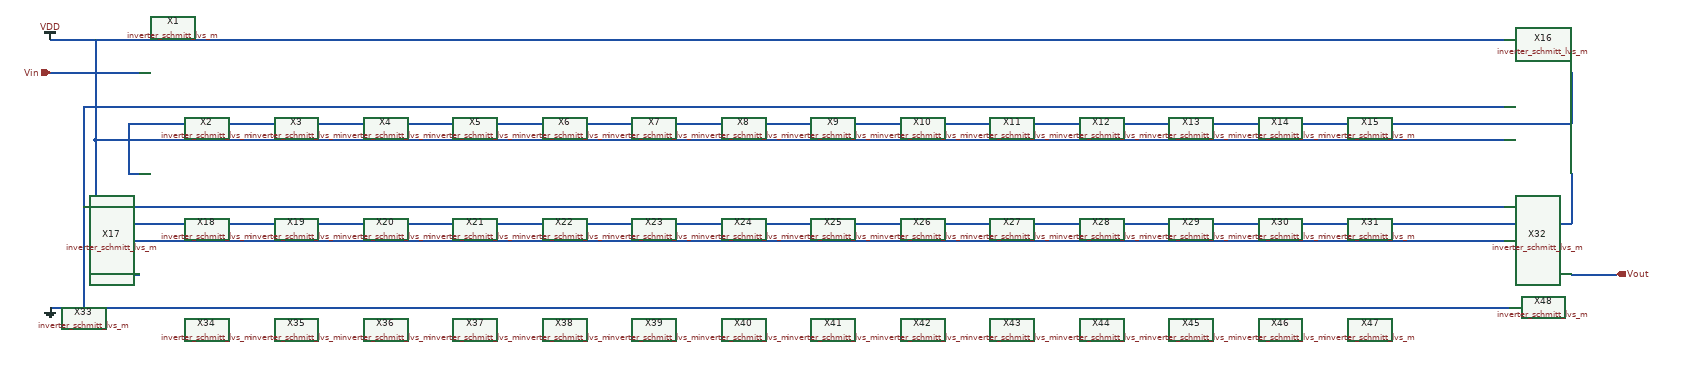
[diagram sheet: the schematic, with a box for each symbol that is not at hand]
v {xschem version=2.9.9 file_version=1.2 }
G {}
K {}
V {}
S {}
E {}
N 80 -540 2680 -540 { lab=VDD}
N 160 -360 2680 -360 { lab=VDD}
N 160 -540 160 -360 { lab=VDD}
N 160 -180 2680 -180 { lab=VDD}
N 160 -360 160 -180 { lab=VDD}
N 140 -420 280 -420 { lab=GND}
N 280 -420 2680 -420 { lab=GND}
N 140 -240 2680 -240 { lab=GND}
N 80 -60 2690 -60 { lab=GND}
N 140 -420 140 -60 { lab=GND}
N 2800 -480 2800 -390 { lab=#net1}
N 220 -390 2800 -390 { lab=#net1}
N 220 -390 220 -300 { lab=#net1}
N 220 -300 230 -300 { lab=#net1}
N 230 -300 240 -300 { lab=#net1}
N 2800 -300 2800 -210 { lab=#net2}
N 230 -210 2800 -210 { lab=#net2}
N 220 -210 230 -210 { lab=#net2}
N 220 -210 220 -120 { lab=#net2}
N 230 -120 240 -120 { lab=#net2}
N 220 -120 230 -120 { lab=#net2}
N 2800 -120 2880 -120 { lab=Vout}
N 80 -480 240 -480 { lab=Vin}
C {devices/ipin.sym} 80 -480 0 0 {name=p1 lab=Vin}
C {devices/opin.sym} 2880 -120 0 0 {name=p4 lab=Vout}
C {madvlsi/vdd.sym} 80 -540 0 0 {name=l1 lab=VDD}
C {madvlsi/gnd.sym} 80 -60 0 0 {name=l2 lab=GND}
C {/home/madvlsi/Desktop/MADVLSI_final/schematics/inverter_schmitt_lvs_m.sym} 200 -380 0 0 {name=X1}
C {/home/madvlsi/Desktop/MADVLSI_final/schematics/inverter_schmitt_lvs_m.sym} 360 -380 0 0 {name=X2}
C {/home/madvlsi/Desktop/MADVLSI_final/schematics/inverter_schmitt_lvs_m.sym} 520 -380 0 0 {name=X3}
C {/home/madvlsi/Desktop/MADVLSI_final/schematics/inverter_schmitt_lvs_m.sym} 680 -380 0 0 {name=X4}
C {/home/madvlsi/Desktop/MADVLSI_final/schematics/inverter_schmitt_lvs_m.sym} 840 -380 0 0 {name=X5}
C {/home/madvlsi/Desktop/MADVLSI_final/schematics/inverter_schmitt_lvs_m.sym} 1000 -380 0 0 {name=X6}
C {/home/madvlsi/Desktop/MADVLSI_final/schematics/inverter_schmitt_lvs_m.sym} 1160 -380 0 0 {name=X7}
C {/home/madvlsi/Desktop/MADVLSI_final/schematics/inverter_schmitt_lvs_m.sym} 1320 -380 0 0 {name=X8}
C {/home/madvlsi/Desktop/MADVLSI_final/schematics/inverter_schmitt_lvs_m.sym} 1480 -380 0 0 {name=X9}
C {/home/madvlsi/Desktop/MADVLSI_final/schematics/inverter_schmitt_lvs_m.sym} 1640 -380 0 0 {name=X10}
C {/home/madvlsi/Desktop/MADVLSI_final/schematics/inverter_schmitt_lvs_m.sym} 1800 -380 0 0 {name=X11}
C {/home/madvlsi/Desktop/MADVLSI_final/schematics/inverter_schmitt_lvs_m.sym} 1960 -380 0 0 {name=X12}
C {/home/madvlsi/Desktop/MADVLSI_final/schematics/inverter_schmitt_lvs_m.sym} 2120 -380 0 0 {name=X13}
C {/home/madvlsi/Desktop/MADVLSI_final/schematics/inverter_schmitt_lvs_m.sym} 2280 -380 0 0 {name=X14}
C {/home/madvlsi/Desktop/MADVLSI_final/schematics/inverter_schmitt_lvs_m.sym} 2440 -380 0 0 {name=X15}
C {/home/madvlsi/Desktop/MADVLSI_final/schematics/inverter_schmitt_lvs_m.sym} 2600 -380 0 0 {name=X16}
C {/home/madvlsi/Desktop/MADVLSI_final/schematics/inverter_schmitt_lvs_m.sym} 200 -200 0 0 {name=X17}
C {/home/madvlsi/Desktop/MADVLSI_final/schematics/inverter_schmitt_lvs_m.sym} 360 -200 0 0 {name=X18}
C {/home/madvlsi/Desktop/MADVLSI_final/schematics/inverter_schmitt_lvs_m.sym} 520 -200 0 0 {name=X19}
C {/home/madvlsi/Desktop/MADVLSI_final/schematics/inverter_schmitt_lvs_m.sym} 680 -200 0 0 {name=X20}
C {/home/madvlsi/Desktop/MADVLSI_final/schematics/inverter_schmitt_lvs_m.sym} 840 -200 0 0 {name=X21}
C {/home/madvlsi/Desktop/MADVLSI_final/schematics/inverter_schmitt_lvs_m.sym} 1000 -200 0 0 {name=X22}
C {/home/madvlsi/Desktop/MADVLSI_final/schematics/inverter_schmitt_lvs_m.sym} 1160 -200 0 0 {name=X23}
C {/home/madvlsi/Desktop/MADVLSI_final/schematics/inverter_schmitt_lvs_m.sym} 1320 -200 0 0 {name=X24}
C {/home/madvlsi/Desktop/MADVLSI_final/schematics/inverter_schmitt_lvs_m.sym} 1480 -200 0 0 {name=X25}
C {/home/madvlsi/Desktop/MADVLSI_final/schematics/inverter_schmitt_lvs_m.sym} 1640 -200 0 0 {name=X26}
C {/home/madvlsi/Desktop/MADVLSI_final/schematics/inverter_schmitt_lvs_m.sym} 1800 -200 0 0 {name=X27}
C {/home/madvlsi/Desktop/MADVLSI_final/schematics/inverter_schmitt_lvs_m.sym} 1960 -200 0 0 {name=X28}
C {/home/madvlsi/Desktop/MADVLSI_final/schematics/inverter_schmitt_lvs_m.sym} 2120 -200 0 0 {name=X29}
C {/home/madvlsi/Desktop/MADVLSI_final/schematics/inverter_schmitt_lvs_m.sym} 2280 -200 0 0 {name=X30}
C {/home/madvlsi/Desktop/MADVLSI_final/schematics/inverter_schmitt_lvs_m.sym} 2440 -200 0 0 {name=X31}
C {/home/madvlsi/Desktop/MADVLSI_final/schematics/inverter_schmitt_lvs_m.sym} 2600 -200 0 0 {name=X32}
C {/home/madvlsi/Desktop/MADVLSI_final/schematics/inverter_schmitt_lvs_m.sym} 200 -20 0 0 {name=X33}
C {/home/madvlsi/Desktop/MADVLSI_final/schematics/inverter_schmitt_lvs_m.sym} 360 -20 0 0 {name=X34}
C {/home/madvlsi/Desktop/MADVLSI_final/schematics/inverter_schmitt_lvs_m.sym} 520 -20 0 0 {name=X35}
C {/home/madvlsi/Desktop/MADVLSI_final/schematics/inverter_schmitt_lvs_m.sym} 680 -20 0 0 {name=X36}
C {/home/madvlsi/Desktop/MADVLSI_final/schematics/inverter_schmitt_lvs_m.sym} 840 -20 0 0 {name=X37}
C {/home/madvlsi/Desktop/MADVLSI_final/schematics/inverter_schmitt_lvs_m.sym} 1000 -20 0 0 {name=X38}
C {/home/madvlsi/Desktop/MADVLSI_final/schematics/inverter_schmitt_lvs_m.sym} 1160 -20 0 0 {name=X39}
C {/home/madvlsi/Desktop/MADVLSI_final/schematics/inverter_schmitt_lvs_m.sym} 1320 -20 0 0 {name=X40}
C {/home/madvlsi/Desktop/MADVLSI_final/schematics/inverter_schmitt_lvs_m.sym} 1480 -20 0 0 {name=X41}
C {/home/madvlsi/Desktop/MADVLSI_final/schematics/inverter_schmitt_lvs_m.sym} 1640 -20 0 0 {name=X42}
C {/home/madvlsi/Desktop/MADVLSI_final/schematics/inverter_schmitt_lvs_m.sym} 1800 -20 0 0 {name=X43}
C {/home/madvlsi/Desktop/MADVLSI_final/schematics/inverter_schmitt_lvs_m.sym} 1960 -20 0 0 {name=X44}
C {/home/madvlsi/Desktop/MADVLSI_final/schematics/inverter_schmitt_lvs_m.sym} 2120 -20 0 0 {name=X45}
C {/home/madvlsi/Desktop/MADVLSI_final/schematics/inverter_schmitt_lvs_m.sym} 2280 -20 0 0 {name=X46}
C {/home/madvlsi/Desktop/MADVLSI_final/schematics/inverter_schmitt_lvs_m.sym} 2440 -20 0 0 {name=X47}
C {/home/madvlsi/Desktop/MADVLSI_final/schematics/inverter_schmitt_lvs_m.sym} 2600 -20 0 0 {name=X48}
